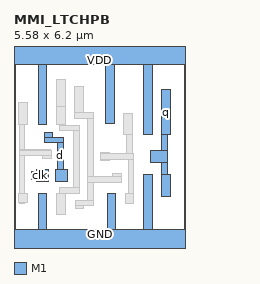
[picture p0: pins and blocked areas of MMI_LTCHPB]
MACRO MMI_LTCHPB
	CLASS CORE ;
	FOREIGN MMI_LTCHPB 0 0 ;
	SIZE 5.58 BY 6.2 ;
	SYMMETRY X Y ;
	SITE CORE1 ;
	PIN d
		DIRECTION input ;
		USE SIGNAL ;
		PORT
			LAYER M1 ;
			RECT 0.99 3.425 1.27 3.58 ;
			LAYER M1 ;
			RECT 0.99 3.235 1.605 3.425 ;
			LAYER M1 ;
			RECT 1.41 2.38 1.605 3.235 ;
			LAYER M1 ;
			RECT 1.34 2.355 1.62 2.38 ;
			LAYER M1 ;
			RECT 1.34 1.98 1.74 2.355 ;
		END
		AntennaGateArea 0.3465 ;
	END d
	PIN GND
		DIRECTION inout ;
		USE GROUND ;
		PORT
			LAYER M1 ;
			RECT 0.795 0.42 1.075 1.59 ;
			LAYER M1 ;
			RECT 3.035 0.42 3.315 1.57 ;
			LAYER M1 ;
			RECT 4.225 0.42 4.505 2.195 ;
			LAYER M1 ;
			RECT 0 -0.42 5.58 0.42 ;
		END
	END GND
	PIN q
		DIRECTION output ;
		USE SIGNAL ;
		PORT
			LAYER M1 ;
			RECT 4.815 3.505 5.095 4.975 ;
			LAYER M1 ;
			RECT 4.82 2.98 5.01 3.505 ;
			LAYER M1 ;
			RECT 4.46 2.6 5.01 2.98 ;
			LAYER M1 ;
			RECT 4.82 2.195 5.01 2.6 ;
			LAYER M1 ;
			RECT 4.815 1.495 5.095 2.195 ;
		END
		AntennaDiffArea 0.91245 ;
	END q
	PIN VDD
		DIRECTION inout ;
		USE POWER ;
		PORT
			LAYER M1 ;
			RECT 0 5.78 5.58 6.62 ;
			LAYER M1 ;
			RECT 0.795 3.84 1.075 5.78 ;
			LAYER M1 ;
			RECT 2.995 3.86 3.275 5.78 ;
			LAYER M1 ;
			RECT 4.225 3.505 4.505 5.78 ;
		END
	END VDD
	PIN clk
		DIRECTION input ;
		USE CLOCK ;
		PORT
			LAYER M1 ;
			RECT 0.735 2.305 1.12 2.355 ;
			LAYER M1 ;
			RECT 0.575 2.025 1.12 2.305 ;
			LAYER M1 ;
			RECT 0.735 1.98 1.12 2.025 ;
		END
		AntennaGateArea 0.34125 ;
	END clk
	OBS
		LAYER M1 ;
		RECT 0.16 3.84 0.44 4.54 ;
		LAYER M1 ;
		RECT 1.385 4.435 1.665 5.31 ;
		LAYER M1 ;
		RECT 1.385 3.84 1.67 4.435 ;
		LAYER M1 ;
		RECT 1.98 4.21 2.26 5.075 ;
		LAYER M1 ;
		RECT 1.98 4.015 2.6 4.21 ;
		LAYER M1 ;
		RECT 0.165 3.015 0.355 3.84 ;
		LAYER M1 ;
		RECT 1.475 3.815 1.67 3.84 ;
		LAYER M1 ;
		RECT 1.475 3.625 2.145 3.815 ;
		LAYER M1 ;
		RECT 0.165 2.99 1.195 3.015 ;
		LAYER M1 ;
		RECT 0.165 2.825 1.21 2.99 ;
		LAYER M1 ;
		RECT 0.165 1.59 0.355 2.825 ;
		LAYER M1 ;
		RECT 0.93 2.71 1.21 2.825 ;
		LAYER M1 ;
		RECT 1.95 1.77 2.145 3.625 ;
		LAYER M1 ;
		RECT 1.475 1.59 2.145 1.77 ;
		LAYER M1 ;
		RECT 0.16 1.275 0.44 1.59 ;
		LAYER M1 ;
		RECT 0.165 1.255 0.355 1.275 ;
		LAYER M1 ;
		RECT 1.385 1.58 2.145 1.59 ;
		LAYER M1 ;
		RECT 2.405 2.135 2.6 4.015 ;
		LAYER M1 ;
		RECT 3.585 3.505 3.865 4.205 ;
		LAYER M1 ;
		RECT 2.825 2.885 3.105 2.925 ;
		LAYER M1 ;
		RECT 3.67 2.885 3.865 3.505 ;
		LAYER M1 ;
		RECT 2.825 2.695 3.915 2.885 ;
		LAYER M1 ;
		RECT 2.825 2.645 3.105 2.695 ;
		LAYER M1 ;
		RECT 3.23 2.135 3.51 2.22 ;
		LAYER M1 ;
		RECT 2.405 1.94 3.51 2.135 ;
		LAYER M1 ;
		RECT 1.385 0.89 1.665 1.58 ;
		LAYER M1 ;
		RECT 2.405 1.37 2.6 1.94 ;
		LAYER M1 ;
		RECT 3.72 1.57 3.915 2.695 ;
		LAYER M1 ;
		RECT 2.09 1.365 2.6 1.37 ;
		LAYER M1 ;
		RECT 1.995 1.175 2.6 1.365 ;
		LAYER M1 ;
		RECT 1.995 1.085 2.275 1.175 ;
		LAYER M1 ;
		RECT 3.625 1.255 3.915 1.57 ;
		LAYER M1 ;
		RECT 3.72 1.25 3.915 1.255 ;
	END
END MMI_LTCHPB
